One B-rep face of a CAD part: STEP entity #35.
In plain terms, the planar face has unit normal (-1, 0, 0).
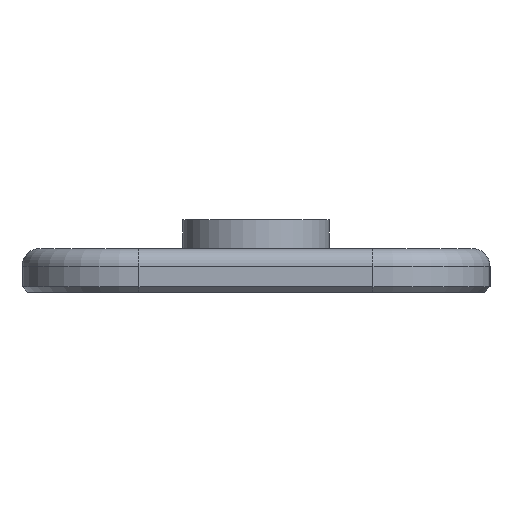
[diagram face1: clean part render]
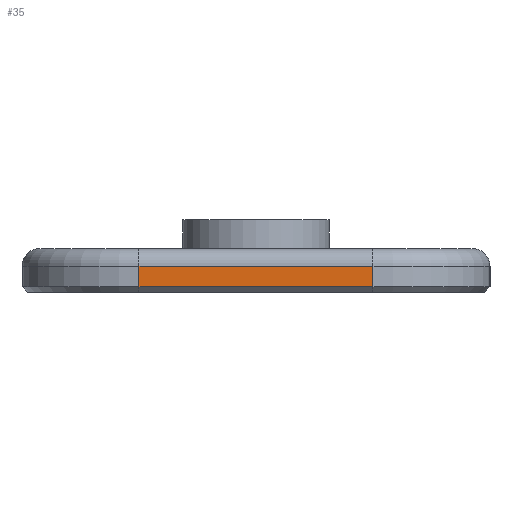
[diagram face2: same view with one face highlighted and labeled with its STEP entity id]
Its self-contained STEP definition (entity closure, numbers rounded to 3 decimals):
#35 = ADVANCED_FACE('',(#36),#50,.T.);
#36 = FACE_BOUND('',#37,.T.);
#37 = EDGE_LOOP('',(#38,#73,#101,#129));
#38 = ORIENTED_EDGE('',*,*,#39,.T.);
#39 = EDGE_CURVE('',#40,#42,#44,.T.);
#40 = VERTEX_POINT('',#41);
#41 = CARTESIAN_POINT('',(-94.,-4.,0.2));
#42 = VERTEX_POINT('',#43);
#43 = CARTESIAN_POINT('',(-94.,-4.,0.9));
#44 = SURFACE_CURVE('',#45,(#49,#61),.PCURVE_S1.);
#45 = LINE('',#46,#47);
#46 = CARTESIAN_POINT('',(-94.,-4.,0.));
#47 = VECTOR('',#48,1.);
#48 = DIRECTION('',(0.,0.,1.));
#49 = PCURVE('',#50,#55);
#50 = PLANE('',#51);
#51 = AXIS2_PLACEMENT_3D('',#52,#53,#54);
#52 = CARTESIAN_POINT('',(-94.,-4.,0.));
#53 = DIRECTION('',(-1.,0.,0.));
#54 = DIRECTION('',(0.,1.,0.));
#55 = DEFINITIONAL_REPRESENTATION('',(#56),#60);
#56 = LINE('',#57,#58);
#57 = CARTESIAN_POINT('',(0.,0.));
#58 = VECTOR('',#59,1.);
#59 = DIRECTION('',(0.,-1.));
#60 = ( GEOMETRIC_REPRESENTATION_CONTEXT(2) 
PARAMETRIC_REPRESENTATION_CONTEXT() REPRESENTATION_CONTEXT('2D SPACE',''
  ) );
#61 = PCURVE('',#62,#67);
#62 = CYLINDRICAL_SURFACE('',#63,4.);
#63 = AXIS2_PLACEMENT_3D('',#64,#65,#66);
#64 = CARTESIAN_POINT('',(-90.,-4.,0.));
#65 = DIRECTION('',(0.,0.,-1.));
#66 = DIRECTION('',(-1.,0.,0.));
#67 = DEFINITIONAL_REPRESENTATION('',(#68),#72);
#68 = LINE('',#69,#70);
#69 = CARTESIAN_POINT('',(6.283,0.));
#70 = VECTOR('',#71,1.);
#71 = DIRECTION('',(0.,-1.));
#72 = ( GEOMETRIC_REPRESENTATION_CONTEXT(2) 
PARAMETRIC_REPRESENTATION_CONTEXT() REPRESENTATION_CONTEXT('2D SPACE',''
  ) );
#73 = ORIENTED_EDGE('',*,*,#74,.T.);
#74 = EDGE_CURVE('',#42,#75,#77,.T.);
#75 = VERTEX_POINT('',#76);
#76 = CARTESIAN_POINT('',(-94.,4.,0.9));
#77 = SURFACE_CURVE('',#78,(#82,#89),.PCURVE_S1.);
#78 = LINE('',#79,#80);
#79 = CARTESIAN_POINT('',(-94.,-4.,0.9));
#80 = VECTOR('',#81,1.);
#81 = DIRECTION('',(0.,1.,0.));
#82 = PCURVE('',#50,#83);
#83 = DEFINITIONAL_REPRESENTATION('',(#84),#88);
#84 = LINE('',#85,#86);
#85 = CARTESIAN_POINT('',(0.,-0.9));
#86 = VECTOR('',#87,1.);
#87 = DIRECTION('',(1.,0.));
#88 = ( GEOMETRIC_REPRESENTATION_CONTEXT(2) 
PARAMETRIC_REPRESENTATION_CONTEXT() REPRESENTATION_CONTEXT('2D SPACE',''
  ) );
#89 = PCURVE('',#90,#95);
#90 = CYLINDRICAL_SURFACE('',#91,0.6);
#91 = AXIS2_PLACEMENT_3D('',#92,#93,#94);
#92 = CARTESIAN_POINT('',(-93.4,-4.,0.9));
#93 = DIRECTION('',(0.,1.,0.));
#94 = DIRECTION('',(-1.,0.,0.));
#95 = DEFINITIONAL_REPRESENTATION('',(#96),#100);
#96 = LINE('',#97,#98);
#97 = CARTESIAN_POINT('',(0.,0.));
#98 = VECTOR('',#99,1.);
#99 = DIRECTION('',(0.,1.));
#100 = ( GEOMETRIC_REPRESENTATION_CONTEXT(2) 
PARAMETRIC_REPRESENTATION_CONTEXT() REPRESENTATION_CONTEXT('2D SPACE',''
  ) );
#101 = ORIENTED_EDGE('',*,*,#102,.F.);
#102 = EDGE_CURVE('',#103,#75,#105,.T.);
#103 = VERTEX_POINT('',#104);
#104 = CARTESIAN_POINT('',(-94.,4.,0.2));
#105 = SURFACE_CURVE('',#106,(#110,#117),.PCURVE_S1.);
#106 = LINE('',#107,#108);
#107 = CARTESIAN_POINT('',(-94.,4.,0.));
#108 = VECTOR('',#109,1.);
#109 = DIRECTION('',(0.,0.,1.));
#110 = PCURVE('',#50,#111);
#111 = DEFINITIONAL_REPRESENTATION('',(#112),#116);
#112 = LINE('',#113,#114);
#113 = CARTESIAN_POINT('',(8.,0.));
#114 = VECTOR('',#115,1.);
#115 = DIRECTION('',(0.,-1.));
#116 = ( GEOMETRIC_REPRESENTATION_CONTEXT(2) 
PARAMETRIC_REPRESENTATION_CONTEXT() REPRESENTATION_CONTEXT('2D SPACE',''
  ) );
#117 = PCURVE('',#118,#123);
#118 = CYLINDRICAL_SURFACE('',#119,4.);
#119 = AXIS2_PLACEMENT_3D('',#120,#121,#122);
#120 = CARTESIAN_POINT('',(-90.,4.,0.));
#121 = DIRECTION('',(0.,0.,-1.));
#122 = DIRECTION('',(-1.,0.,0.));
#123 = DEFINITIONAL_REPRESENTATION('',(#124),#128);
#124 = LINE('',#125,#126);
#125 = CARTESIAN_POINT('',(0.,0.));
#126 = VECTOR('',#127,1.);
#127 = DIRECTION('',(0.,-1.));
#128 = ( GEOMETRIC_REPRESENTATION_CONTEXT(2) 
PARAMETRIC_REPRESENTATION_CONTEXT() REPRESENTATION_CONTEXT('2D SPACE',''
  ) );
#129 = ORIENTED_EDGE('',*,*,#130,.F.);
#130 = EDGE_CURVE('',#40,#103,#131,.T.);
#131 = SURFACE_CURVE('',#132,(#136,#143),.PCURVE_S1.);
#132 = LINE('',#133,#134);
#133 = CARTESIAN_POINT('',(-94.,-4.,0.2));
#134 = VECTOR('',#135,1.);
#135 = DIRECTION('',(0.,1.,0.));
#136 = PCURVE('',#50,#137);
#137 = DEFINITIONAL_REPRESENTATION('',(#138),#142);
#138 = LINE('',#139,#140);
#139 = CARTESIAN_POINT('',(0.,-0.2));
#140 = VECTOR('',#141,1.);
#141 = DIRECTION('',(1.,0.));
#142 = ( GEOMETRIC_REPRESENTATION_CONTEXT(2) 
PARAMETRIC_REPRESENTATION_CONTEXT() REPRESENTATION_CONTEXT('2D SPACE',''
  ) );
#143 = PCURVE('',#144,#149);
#144 = PLANE('',#145);
#145 = AXIS2_PLACEMENT_3D('',#146,#147,#148);
#146 = CARTESIAN_POINT('',(-93.9,-4.,0.1));
#147 = DIRECTION('',(0.707,0.,0.707)
  );
#148 = DIRECTION('',(0.,-1.,0.));
#149 = DEFINITIONAL_REPRESENTATION('',(#150),#154);
#150 = LINE('',#151,#152);
#151 = CARTESIAN_POINT('',(-0.,-0.141));
#152 = VECTOR('',#153,1.);
#153 = DIRECTION('',(-1.,0.));
#154 = ( GEOMETRIC_REPRESENTATION_CONTEXT(2) 
PARAMETRIC_REPRESENTATION_CONTEXT() REPRESENTATION_CONTEXT('2D SPACE',''
  ) );
